VERSION 5.8 ;
BUSBITCHARS "[]" ;
DIVIDERCHAR "/" ;

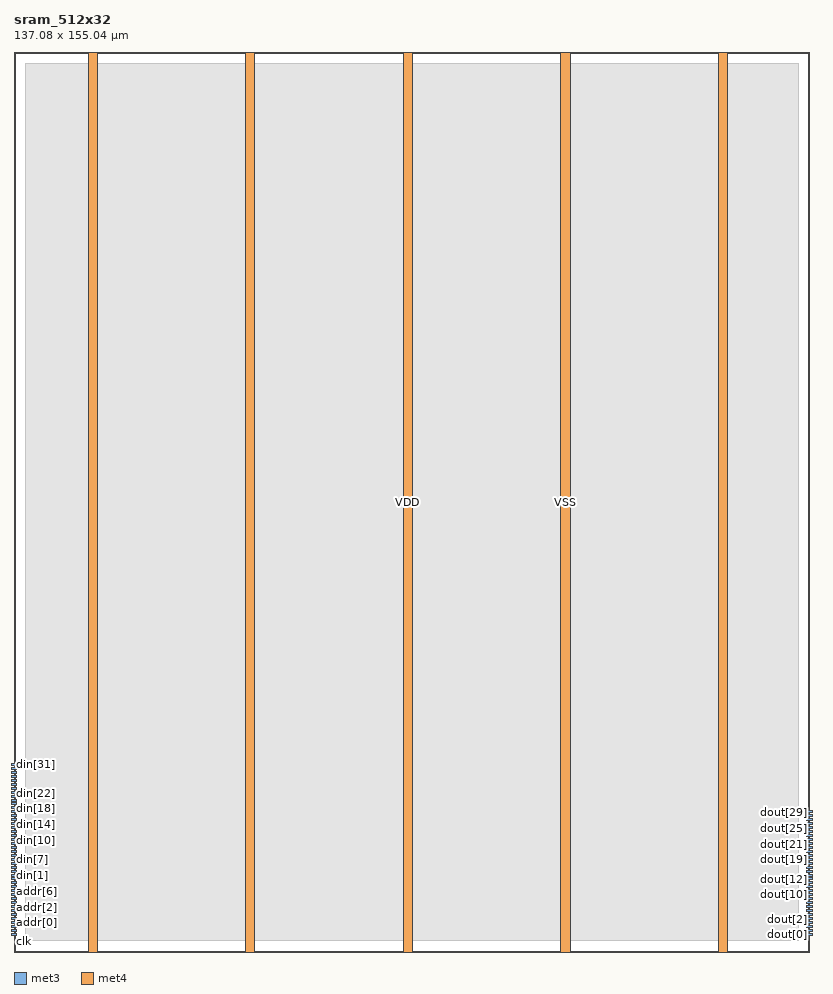
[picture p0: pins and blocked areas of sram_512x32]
MACRO sram_512x32
  CLASS BLOCK ;
  ORIGIN 0 0 ;
  SIZE 137.080 BY 155.040 ;
  SYMMETRY X Y ;

  PIN clk
    DIRECTION INPUT ;
    USE CLOCK ;
    PORT
      LAYER met3 ;
        RECT -0.500 2.890 0.500 3.230 ;
    END
  END clk

  PIN ce
    DIRECTION INPUT ;
    USE SIGNAL ;
    PORT
      LAYER met3 ;
        RECT -0.500 3.570 0.500 3.910 ;
    END
  END ce

  PIN we
    DIRECTION INPUT ;
    USE SIGNAL ;
    PORT
      LAYER met3 ;
        RECT -0.500 4.250 0.500 4.590 ;
    END
  END we

  PIN addr[0]
    DIRECTION INPUT ;
    USE SIGNAL ;
    PORT
      LAYER met3 ;
        RECT -0.500 4.930 0.500 5.270 ;
    END
  END addr[0]

  PIN addr[1]
    DIRECTION INPUT ;
    USE SIGNAL ;
    PORT
      LAYER met3 ;
        RECT -0.500 5.610 0.500 5.950 ;
    END
  END addr[1]

  PIN addr[2]
    DIRECTION INPUT ;
    USE SIGNAL ;
    PORT
      LAYER met3 ;
        RECT -0.500 6.290 0.500 6.630 ;
    END
  END addr[2]

  PIN addr[3]
    DIRECTION INPUT ;
    USE SIGNAL ;
    PORT
      LAYER met3 ;
        RECT -0.500 6.970 0.500 7.310 ;
    END
  END addr[3]

  PIN addr[4]
    DIRECTION INPUT ;
    USE SIGNAL ;
    PORT
      LAYER met3 ;
        RECT -0.500 7.650 0.500 7.990 ;
    END
  END addr[4]

  PIN addr[5]
    DIRECTION INPUT ;
    USE SIGNAL ;
    PORT
      LAYER met3 ;
        RECT -0.500 8.330 0.500 8.670 ;
    END
  END addr[5]

  PIN addr[6]
    DIRECTION INPUT ;
    USE SIGNAL ;
    PORT
      LAYER met3 ;
        RECT -0.500 9.010 0.500 9.350 ;
    END
  END addr[6]

  PIN addr[7]
    DIRECTION INPUT ;
    USE SIGNAL ;
    PORT
      LAYER met3 ;
        RECT -0.500 9.690 0.500 10.030 ;
    END
  END addr[7]

  PIN addr[8]
    DIRECTION INPUT ;
    USE SIGNAL ;
    PORT
      LAYER met3 ;
        RECT -0.500 10.370 0.500 10.710 ;
    END
  END addr[8]

  PIN din[0]
    DIRECTION INPUT ;
    USE SIGNAL ;
    PORT
      LAYER met3 ;
        RECT -0.500 11.050 0.500 11.390 ;
    END
  END din[0]

  PIN din[1]
    DIRECTION INPUT ;
    USE SIGNAL ;
    PORT
      LAYER met3 ;
        RECT -0.500 11.730 0.500 12.070 ;
    END
  END din[1]

  PIN din[2]
    DIRECTION INPUT ;
    USE SIGNAL ;
    PORT
      LAYER met3 ;
        RECT -0.500 12.410 0.500 12.750 ;
    END
  END din[2]

  PIN din[3]
    DIRECTION INPUT ;
    USE SIGNAL ;
    PORT
      LAYER met3 ;
        RECT -0.500 13.090 0.500 13.430 ;
    END
  END din[3]

  PIN din[4]
    DIRECTION INPUT ;
    USE SIGNAL ;
    PORT
      LAYER met3 ;
        RECT -0.500 13.770 0.500 14.110 ;
    END
  END din[4]

  PIN din[5]
    DIRECTION INPUT ;
    USE SIGNAL ;
    PORT
      LAYER met3 ;
        RECT -0.500 14.450 0.500 14.790 ;
    END
  END din[5]

  PIN din[6]
    DIRECTION INPUT ;
    USE SIGNAL ;
    PORT
      LAYER met3 ;
        RECT -0.500 15.130 0.500 15.470 ;
    END
  END din[6]

  PIN din[7]
    DIRECTION INPUT ;
    USE SIGNAL ;
    PORT
      LAYER met3 ;
        RECT -0.500 15.810 0.500 16.150 ;
    END
  END din[7]

  PIN din[8]
    DIRECTION INPUT ;
    USE SIGNAL ;
    PORT
      LAYER met3 ;
        RECT -0.500 16.490 0.500 16.830 ;
    END
  END din[8]

  PIN din[9]
    DIRECTION INPUT ;
    USE SIGNAL ;
    PORT
      LAYER met3 ;
        RECT -0.500 17.170 0.500 17.510 ;
    END
  END din[9]

  PIN din[10]
    DIRECTION INPUT ;
    USE SIGNAL ;
    PORT
      LAYER met3 ;
        RECT -0.500 17.850 0.500 18.190 ;
    END
  END din[10]

  PIN din[11]
    DIRECTION INPUT ;
    USE SIGNAL ;
    PORT
      LAYER met3 ;
        RECT -0.500 18.530 0.500 18.870 ;
    END
  END din[11]

  PIN din[12]
    DIRECTION INPUT ;
    USE SIGNAL ;
    PORT
      LAYER met3 ;
        RECT -0.500 19.210 0.500 19.550 ;
    END
  END din[12]

  PIN din[13]
    DIRECTION INPUT ;
    USE SIGNAL ;
    PORT
      LAYER met3 ;
        RECT -0.500 19.890 0.500 20.230 ;
    END
  END din[13]

  PIN din[14]
    DIRECTION INPUT ;
    USE SIGNAL ;
    PORT
      LAYER met3 ;
        RECT -0.500 20.570 0.500 20.910 ;
    END
  END din[14]

  PIN din[15]
    DIRECTION INPUT ;
    USE SIGNAL ;
    PORT
      LAYER met3 ;
        RECT -0.500 21.250 0.500 21.590 ;
    END
  END din[15]

  PIN din[16]
    DIRECTION INPUT ;
    USE SIGNAL ;
    PORT
      LAYER met3 ;
        RECT -0.500 21.930 0.500 22.270 ;
    END
  END din[16]

  PIN din[17]
    DIRECTION INPUT ;
    USE SIGNAL ;
    PORT
      LAYER met3 ;
        RECT -0.500 22.610 0.500 22.950 ;
    END
  END din[17]

  PIN din[18]
    DIRECTION INPUT ;
    USE SIGNAL ;
    PORT
      LAYER met3 ;
        RECT -0.500 23.290 0.500 23.630 ;
    END
  END din[18]

  PIN din[19]
    DIRECTION INPUT ;
    USE SIGNAL ;
    PORT
      LAYER met3 ;
        RECT -0.500 23.970 0.500 24.310 ;
    END
  END din[19]

  PIN din[20]
    DIRECTION INPUT ;
    USE SIGNAL ;
    PORT
      LAYER met3 ;
        RECT -0.500 24.650 0.500 24.990 ;
    END
  END din[20]

  PIN din[21]
    DIRECTION INPUT ;
    USE SIGNAL ;
    PORT
      LAYER met3 ;
        RECT -0.500 25.330 0.500 25.670 ;
    END
  END din[21]

  PIN din[22]
    DIRECTION INPUT ;
    USE SIGNAL ;
    PORT
      LAYER met3 ;
        RECT -0.500 26.010 0.500 26.350 ;
    END
  END din[22]

  PIN din[23]
    DIRECTION INPUT ;
    USE SIGNAL ;
    PORT
      LAYER met3 ;
        RECT -0.500 26.690 0.500 27.030 ;
    END
  END din[23]

  PIN din[24]
    DIRECTION INPUT ;
    USE SIGNAL ;
    PORT
      LAYER met3 ;
        RECT -0.500 27.370 0.500 27.710 ;
    END
  END din[24]

  PIN din[25]
    DIRECTION INPUT ;
    USE SIGNAL ;
    PORT
      LAYER met3 ;
        RECT -0.500 28.050 0.500 28.390 ;
    END
  END din[25]

  PIN din[26]
    DIRECTION INPUT ;
    USE SIGNAL ;
    PORT
      LAYER met3 ;
        RECT -0.500 28.730 0.500 29.070 ;
    END
  END din[26]

  PIN din[27]
    DIRECTION INPUT ;
    USE SIGNAL ;
    PORT
      LAYER met3 ;
        RECT -0.500 29.410 0.500 29.750 ;
    END
  END din[27]

  PIN din[28]
    DIRECTION INPUT ;
    USE SIGNAL ;
    PORT
      LAYER met3 ;
        RECT -0.500 30.090 0.500 30.430 ;
    END
  END din[28]

  PIN din[29]
    DIRECTION INPUT ;
    USE SIGNAL ;
    PORT
      LAYER met3 ;
        RECT -0.500 30.770 0.500 31.110 ;
    END
  END din[29]

  PIN din[30]
    DIRECTION INPUT ;
    USE SIGNAL ;
    PORT
      LAYER met3 ;
        RECT -0.500 31.450 0.500 31.790 ;
    END
  END din[30]

  PIN din[31]
    DIRECTION INPUT ;
    USE SIGNAL ;
    PORT
      LAYER met3 ;
        RECT -0.500 32.130 0.500 32.470 ;
    END
  END din[31]

  PIN dout[0]
    DIRECTION OUTPUT ;
    USE SIGNAL ;
    PORT
      LAYER met3 ;
        RECT 136.580 2.890 137.580 3.230 ;
    END
  END dout[0]

  PIN dout[1]
    DIRECTION OUTPUT ;
    USE SIGNAL ;
    PORT
      LAYER met3 ;
        RECT 136.580 3.570 137.580 3.910 ;
    END
  END dout[1]

  PIN dout[2]
    DIRECTION OUTPUT ;
    USE SIGNAL ;
    PORT
      LAYER met3 ;
        RECT 136.580 4.250 137.580 4.590 ;
    END
  END dout[2]

  PIN dout[3]
    DIRECTION OUTPUT ;
    USE SIGNAL ;
    PORT
      LAYER met3 ;
        RECT 136.580 4.930 137.580 5.270 ;
    END
  END dout[3]

  PIN dout[4]
    DIRECTION OUTPUT ;
    USE SIGNAL ;
    PORT
      LAYER met3 ;
        RECT 136.580 5.610 137.580 5.950 ;
    END
  END dout[4]

  PIN dout[5]
    DIRECTION OUTPUT ;
    USE SIGNAL ;
    PORT
      LAYER met3 ;
        RECT 136.580 6.290 137.580 6.630 ;
    END
  END dout[5]

  PIN dout[6]
    DIRECTION OUTPUT ;
    USE SIGNAL ;
    PORT
      LAYER met3 ;
        RECT 136.580 6.970 137.580 7.310 ;
    END
  END dout[6]

  PIN dout[7]
    DIRECTION OUTPUT ;
    USE SIGNAL ;
    PORT
      LAYER met3 ;
        RECT 136.580 7.650 137.580 7.990 ;
    END
  END dout[7]

  PIN dout[8]
    DIRECTION OUTPUT ;
    USE SIGNAL ;
    PORT
      LAYER met3 ;
        RECT 136.580 8.330 137.580 8.670 ;
    END
  END dout[8]

  PIN dout[9]
    DIRECTION OUTPUT ;
    USE SIGNAL ;
    PORT
      LAYER met3 ;
        RECT 136.580 9.010 137.580 9.350 ;
    END
  END dout[9]

  PIN dout[10]
    DIRECTION OUTPUT ;
    USE SIGNAL ;
    PORT
      LAYER met3 ;
        RECT 136.580 9.690 137.580 10.030 ;
    END
  END dout[10]

  PIN dout[11]
    DIRECTION OUTPUT ;
    USE SIGNAL ;
    PORT
      LAYER met3 ;
        RECT 136.580 10.370 137.580 10.710 ;
    END
  END dout[11]

  PIN dout[12]
    DIRECTION OUTPUT ;
    USE SIGNAL ;
    PORT
      LAYER met3 ;
        RECT 136.580 11.050 137.580 11.390 ;
    END
  END dout[12]

  PIN dout[13]
    DIRECTION OUTPUT ;
    USE SIGNAL ;
    PORT
      LAYER met3 ;
        RECT 136.580 11.730 137.580 12.070 ;
    END
  END dout[13]

  PIN dout[14]
    DIRECTION OUTPUT ;
    USE SIGNAL ;
    PORT
      LAYER met3 ;
        RECT 136.580 12.410 137.580 12.750 ;
    END
  END dout[14]

  PIN dout[15]
    DIRECTION OUTPUT ;
    USE SIGNAL ;
    PORT
      LAYER met3 ;
        RECT 136.580 13.090 137.580 13.430 ;
    END
  END dout[15]

  PIN dout[16]
    DIRECTION OUTPUT ;
    USE SIGNAL ;
    PORT
      LAYER met3 ;
        RECT 136.580 13.770 137.580 14.110 ;
    END
  END dout[16]

  PIN dout[17]
    DIRECTION OUTPUT ;
    USE SIGNAL ;
    PORT
      LAYER met3 ;
        RECT 136.580 14.450 137.580 14.790 ;
    END
  END dout[17]

  PIN dout[18]
    DIRECTION OUTPUT ;
    USE SIGNAL ;
    PORT
      LAYER met3 ;
        RECT 136.580 15.130 137.580 15.470 ;
    END
  END dout[18]

  PIN dout[19]
    DIRECTION OUTPUT ;
    USE SIGNAL ;
    PORT
      LAYER met3 ;
        RECT 136.580 15.810 137.580 16.150 ;
    END
  END dout[19]

  PIN dout[20]
    DIRECTION OUTPUT ;
    USE SIGNAL ;
    PORT
      LAYER met3 ;
        RECT 136.580 16.490 137.580 16.830 ;
    END
  END dout[20]

  PIN dout[21]
    DIRECTION OUTPUT ;
    USE SIGNAL ;
    PORT
      LAYER met3 ;
        RECT 136.580 17.170 137.580 17.510 ;
    END
  END dout[21]

  PIN dout[22]
    DIRECTION OUTPUT ;
    USE SIGNAL ;
    PORT
      LAYER met3 ;
        RECT 136.580 17.850 137.580 18.190 ;
    END
  END dout[22]

  PIN dout[23]
    DIRECTION OUTPUT ;
    USE SIGNAL ;
    PORT
      LAYER met3 ;
        RECT 136.580 18.530 137.580 18.870 ;
    END
  END dout[23]

  PIN dout[24]
    DIRECTION OUTPUT ;
    USE SIGNAL ;
    PORT
      LAYER met3 ;
        RECT 136.580 19.210 137.580 19.550 ;
    END
  END dout[24]

  PIN dout[25]
    DIRECTION OUTPUT ;
    USE SIGNAL ;
    PORT
      LAYER met3 ;
        RECT 136.580 19.890 137.580 20.230 ;
    END
  END dout[25]

  PIN dout[26]
    DIRECTION OUTPUT ;
    USE SIGNAL ;
    PORT
      LAYER met3 ;
        RECT 136.580 20.570 137.580 20.910 ;
    END
  END dout[26]

  PIN dout[27]
    DIRECTION OUTPUT ;
    USE SIGNAL ;
    PORT
      LAYER met3 ;
        RECT 136.580 21.250 137.580 21.590 ;
    END
  END dout[27]

  PIN dout[28]
    DIRECTION OUTPUT ;
    USE SIGNAL ;
    PORT
      LAYER met3 ;
        RECT 136.580 21.930 137.580 22.270 ;
    END
  END dout[28]

  PIN dout[29]
    DIRECTION OUTPUT ;
    USE SIGNAL ;
    PORT
      LAYER met3 ;
        RECT 136.580 22.610 137.580 22.950 ;
    END
  END dout[29]

  PIN dout[30]
    DIRECTION OUTPUT ;
    USE SIGNAL ;
    PORT
      LAYER met3 ;
        RECT 136.580 23.290 137.580 23.630 ;
    END
  END dout[30]

  PIN dout[31]
    DIRECTION OUTPUT ;
    USE SIGNAL ;
    PORT
      LAYER met3 ;
        RECT 136.580 23.970 137.580 24.310 ;
    END
  END dout[31]

  PIN VDD
    DIRECTION INOUT ;
    USE POWER ;
    PORT
      LAYER met4 ;
        RECT 12.770 0.000 14.370 155.040 ;
        RECT 67.050 0.000 68.650 155.040 ;
        RECT 121.330 0.000 122.930 155.040 ;
    END
  END VDD

  PIN VSS
    DIRECTION INOUT ;
    USE GROUND ;
    PORT
      LAYER met4 ;
        RECT 39.910 0.000 41.510 155.040 ;
        RECT 94.190 0.000 95.790 155.040 ;
    END
  END VSS

  OBS
    LAYER met1 ;
      RECT 2.000 2.000 135.080 153.040 ;
    LAYER met2 ;
      RECT 2.000 2.000 135.080 153.040 ;
    LAYER met4 ;
      RECT 2.000 2.000 135.080 153.040 ;
  END

END sram_512x32

END LIBRARY
